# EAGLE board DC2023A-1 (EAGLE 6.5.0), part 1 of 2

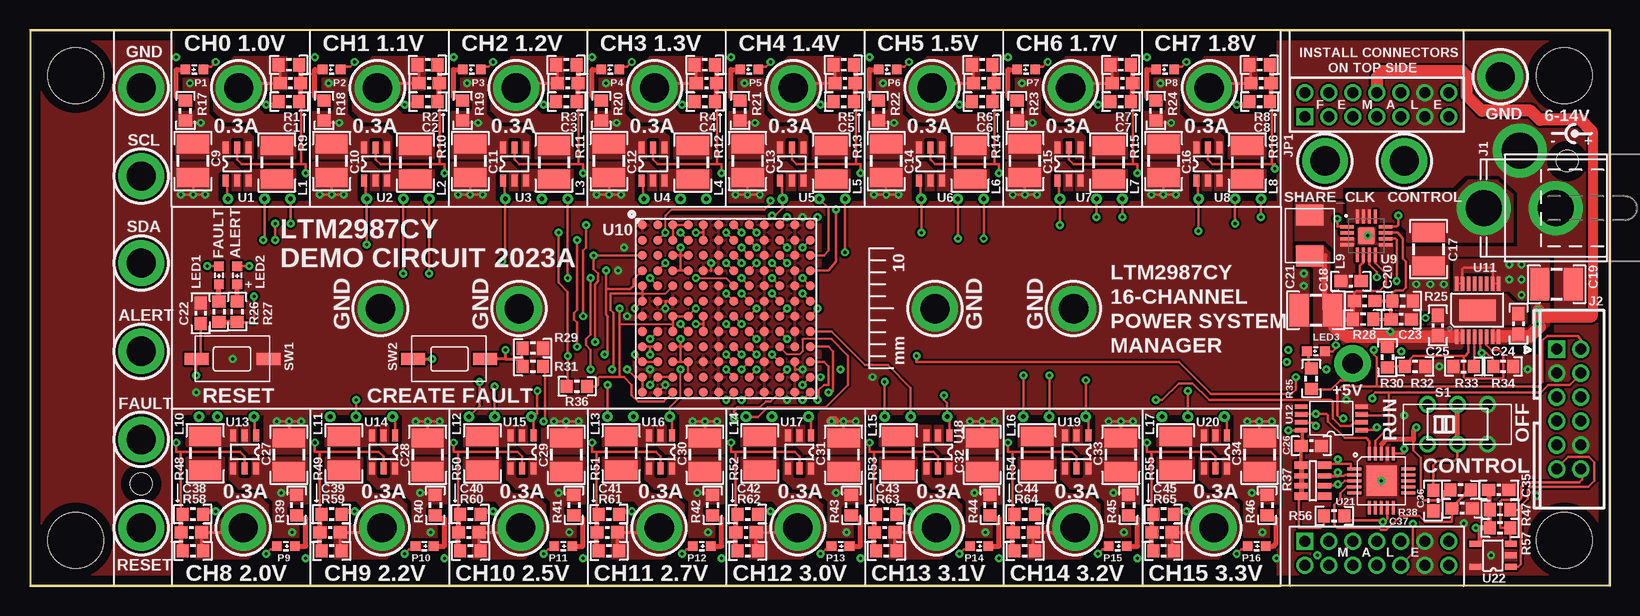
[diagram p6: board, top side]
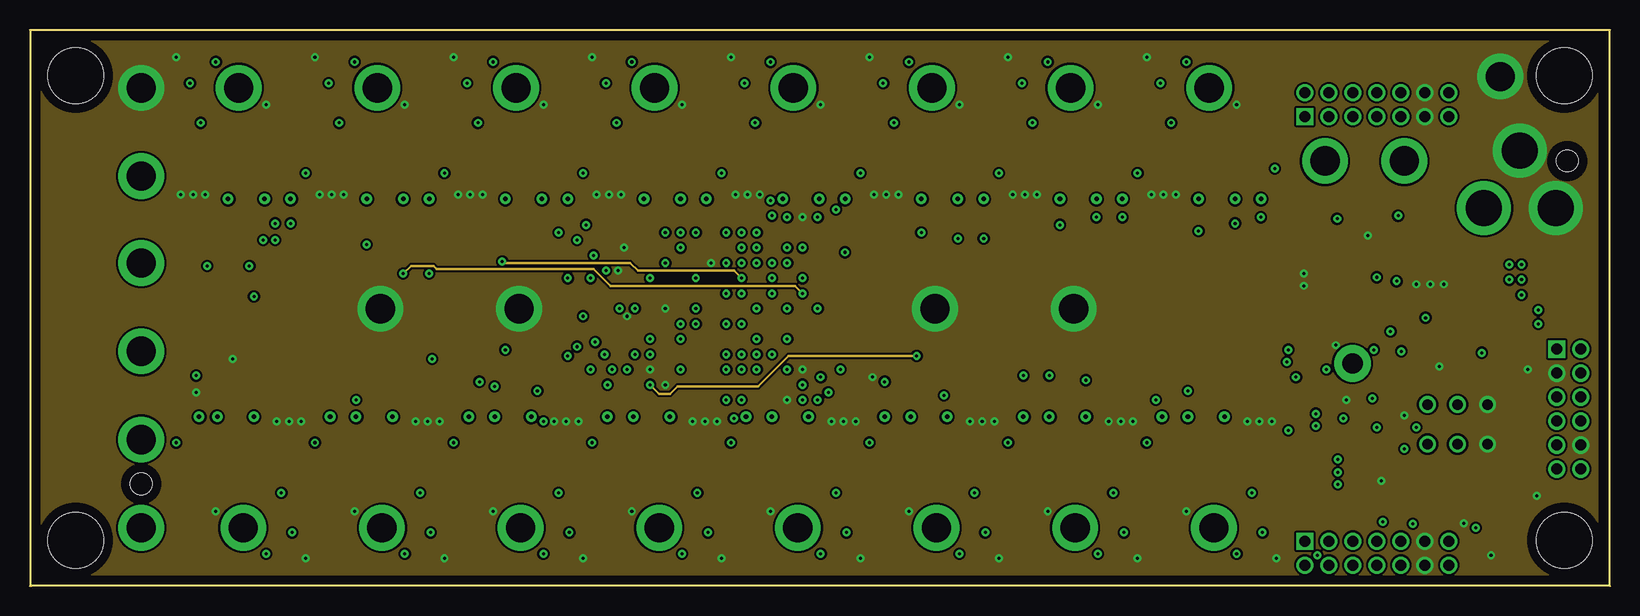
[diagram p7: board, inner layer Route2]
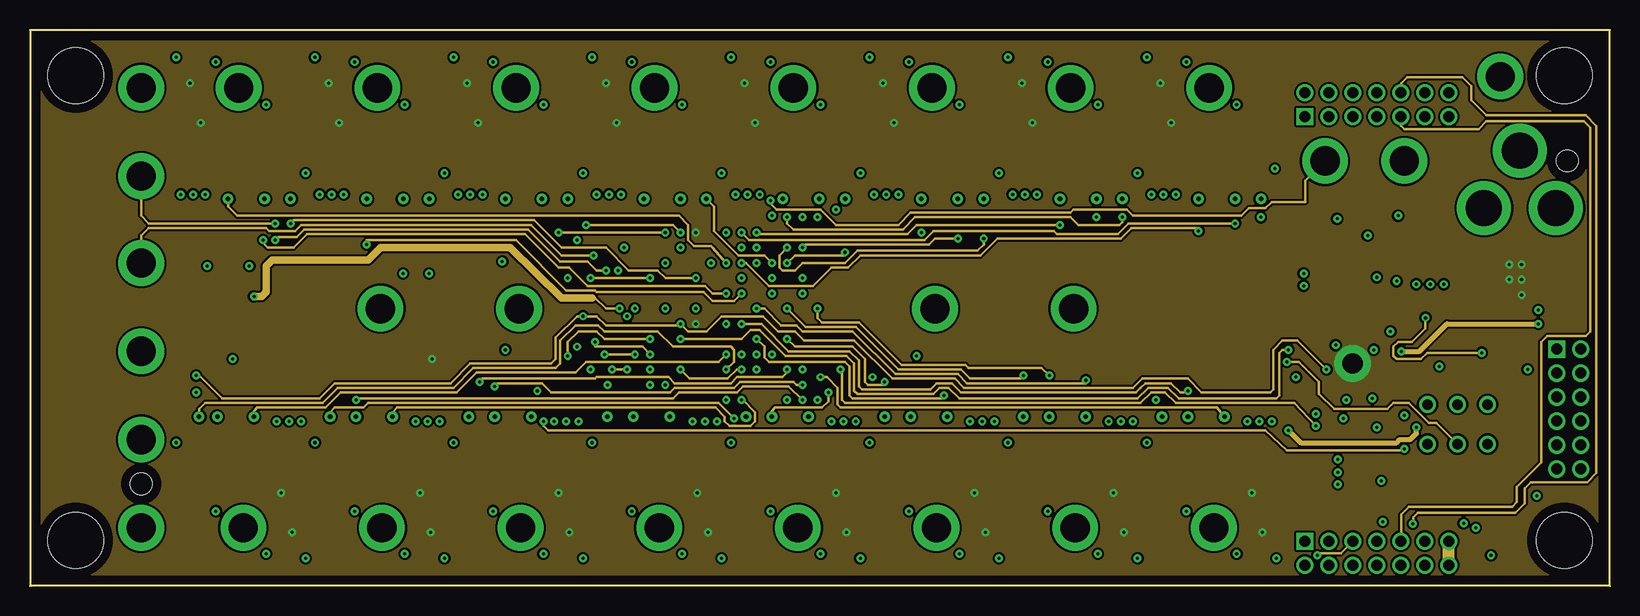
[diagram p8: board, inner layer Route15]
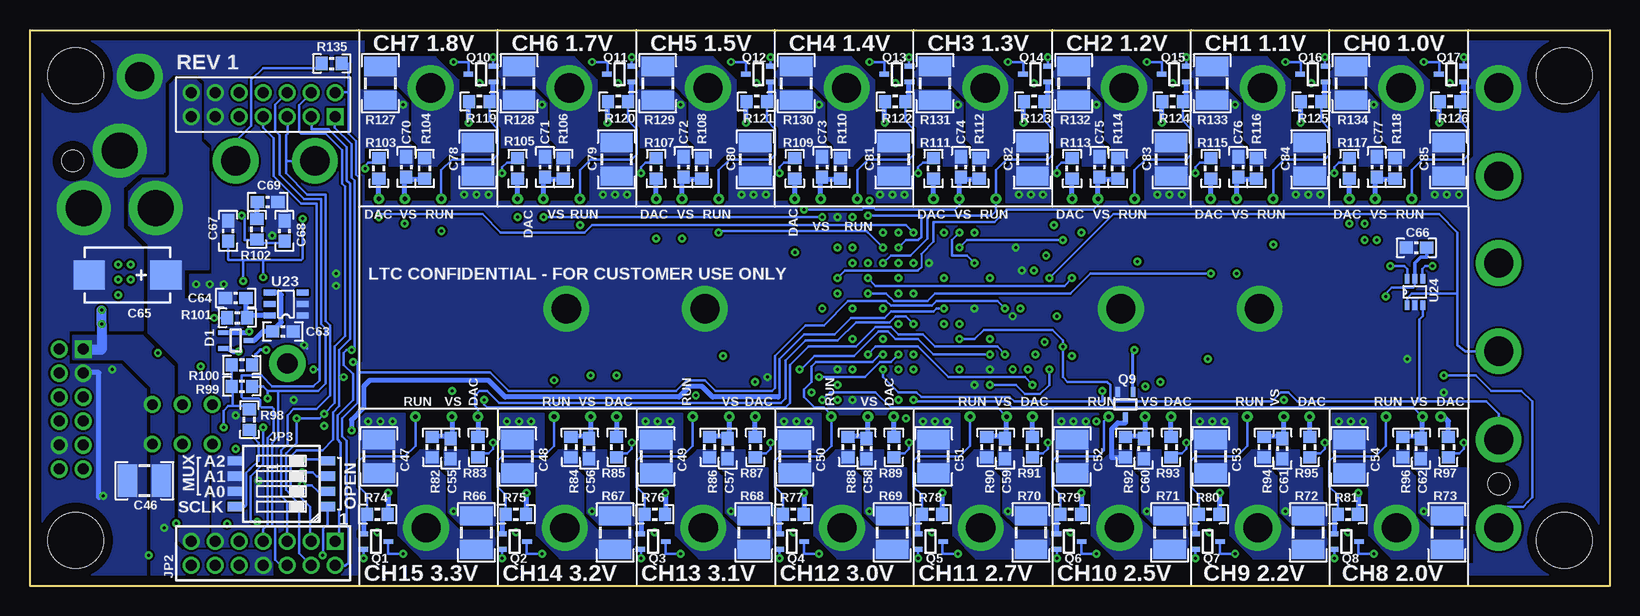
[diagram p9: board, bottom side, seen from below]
Size 131.7 x 46.35 mm. Coordinates in mm from the lower left corner, seen from the top.
Outline: 0,0 0,46.35 131.7,46.35 131.7,0 0.13,0
Copper layers (1*2+15*16): Top 0.035mm / dielectric 1.5mm / Route2 0.035mm / dielectric 0.15mm / Route15 0.035mm / dielectric 0.2mm / Bottom 0.035mm
Design rules "default *": minimum track width 7mil, minimum drill 10mil, track to track 7mil, track to pad 7mil, pad to pad 7mil, via to via 7mil, smd to smd 4mil, copper to edge 30mil, drill to drill 20mil, minimum pad ring 10mil, minimum via ring 8mil, stop-mask expansion 4mil, vias tented up to drill 16mil, thermal gap 10mil
Holes 4.65 mm at 3.81,3.81 3.81,42.55 127.89,42.55 127.89,3.81
Holes 1.8 mm at 9.27,8.51 128.14,35.43

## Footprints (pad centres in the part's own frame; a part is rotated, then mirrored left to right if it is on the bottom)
C0603_BOX = smd 1.1 x 1: 1 -0.85,0; 2 0.85,0
C1210_BOX = smd 1.6 x 2.7: 1 -1.4,0; 2 1.4,0
C7343 = smd 2.6 x 2.4: + -3.2,0; - 3.2,0
SC70-3 = smd 0.4 x 0.8: 1 -0.65,-1.052; 2 0.65,-1.052; 3 0,1.052
PJ-002A = drill 3 pad 4.5: 1 -3,0; 2 0,-4.8; 3 3,0
CONN_DC1613 = drill 0.914 square: 1 -5,-1 | drill 0.914: 2 -5,1; 3 -3,-1; 4 -3,1; 5 -1,-1; 6 -1,1; 7 1,-1; 8 1,1; 9 3,-1; 10 3,1; 11 5,-1; 12 5,1
2X07M = drill 0.914 square: 1 -6,-1 | drill 0.914: 2 -6,1; 3 -4,-1; 4 -4,1; 5 -2,-1; 6 -2,1; 7 0,-1; 8 0,1; 9 2,-1; 10 2,1; 11 4,-1; 12 4,1; 13 6,-1; 14 6,1
SMT_DIP_4 = smd 1.27 x 0.762: 1 -3.861,1.905; 2 -3.861,0.635; 3 -3.861,-0.635; 4 -3.861,-1.905; 5 3.861,-1.905; 6 3.861,-0.635; 7 3.861,0.635; 8 3.861,1.905
L1210 = smd 1.6 x 2.7: 1 -1.4,0; 2 1.4,0
IHLP_1616AB = smd 1.75 x 2.3: 1 -1.7,0; 2 1.7,0
CHIPLED_0603 = smd 0.8 x 0.8: N 0,0.75; P 0,-0.75
R0603_BOX = smd 1 x 1.1: 1 -0.85,0; 2 0.85,0
R_VISHAY_CRA06S = smd 1.15 x 0.63: R1_1 -0.975,1.295; R1_2 0.975,1.295; R4_1 -0.975,-1.295; R4_2 0.975,-1.295 | smd 1.15 x 0.44: R2_1 -0.975,0.4; R2_2 0.975,0.4; R3_1 -0.975,-0.4; R3_2 0.975,-0.4
R1210_BOX = smd 1.6 x 2.7: 1 -1.4,0; 2 1.4,0
JS202011CQN = drill 0.9: 1 -2.5,1.65; 2 0,1.65; 3 2.5,1.65; 4 -2.5,-1.65; 5 0,-1.65; 6 2.5,-1.65
SWITCH_PTS635 = smd 2 x 1: SW1 -3,0; SW2 3,0
TP1 = drill 2.438 pad 3.81: TP 0,0
TURRET_SMALL_2308 = drill 1.702 pad 3.048: TP1 0,0
SOT-23-6 = smd 1 x 0.5: 1 -1.374,1.087; 2 -1.374,0.127; 3 -1.374,-0.833; 4 1.374,-0.833; 5 1.374,0.127; 6 1.374,1.087
QFN16_3X3 = smd 1.2 x 0.3: 1 -1.711,0.734; 2 -1.711,0.234; 3 -1.711,-0.266; 4 -1.711,-0.766; 9 1.489,-0.766; 10 1.489,-0.266; 11 1.489,0.234; 12 1.489,0.734 | smd 0.3 x 1.2: 5 -0.861,-1.616; 6 -0.361,-1.616; 7 0.139,-1.616; 8 0.639,-1.616; 13 0.639,1.584; 14 0.139,1.584; 15 -0.361,1.584; 16 -0.861,1.584 | smd 1.4 x 1.4: PAD -0.111,-0.016
BGA_144_1.27 = smd 0.73 x 0.73: A1 -6.985,-6.985; A2 -6.985,-5.715; A3 -6.985,-4.445; A4 -6.985,-3.175; A5 -6.985,-1.905; A6 -6.985,-0.635; A7 -6.985,0.635; A8 -6.985,1.905; A9 -6.985,3.175; A10 -6.985,4.445; A11 -6.985,5.715; A12 -6.985,6.985; B1 -5.715,-6.985; B2 -5.715,-5.715; B3 -5.715,-4.445; B4 -5.715,-3.175; B5 -5.715,-1.905; B6 -5.715,-0.635; B7 -5.715,0.635; B8 -5.715,1.905; B9 -5.715,3.175; B10 -5.715,4.445; B11 -5.715,5.715; B12 -5.715,6.985; C1 -4.445,-6.985; C2 -4.445,-5.715; C3 -4.445,-4.445; C4 -4.445,-3.175; C5 -4.445,-1.905; C6 -4.445,-0.635; C7 -4.445,0.635; C8 -4.445,1.905; C9 -4.445,3.175; C10 -4.445,4.445; C11 -4.445,5.715; C12 -4.445,6.985; D1 -3.175,-6.985; D2 -3.175,-5.715; D3 -3.175,-4.445; D4 -3.175,-3.175; D5 -3.175,-1.905; D6 -3.175,-0.635; D7 -3.175,0.635; D8 -3.175,1.905; D9 -3.175,3.175; D10 -3.175,4.445; D11 -3.175,5.715; D12 -3.175,6.985; E1 -1.905,-6.985; E2 -1.905,-5.715; E3 -1.905,-4.445; E4 -1.905,-3.175; E5 -1.905,-1.905; E6 -1.905,-0.635; E7 -1.905,0.635; E8 -1.905,1.905; E9 -1.905,3.175; E10 -1.905,4.445; E11 -1.905,5.715; E12 -1.905,6.985; F1 -0.635,-6.985; F2 -0.635,-5.715; F3 -0.635,-4.445; F4 -0.635,-3.175; F5 -0.635,-1.905; F6 -0.635,-0.635; F7 -0.635,0.635; F8 -0.635,1.905; F9 -0.635,3.175; F10 -0.635,4.445; F11 -0.635,5.715; F12 -0.635,6.985; G1 0.635,-6.985; G2 0.635,-5.715; G3 0.635,-4.445; G4 0.635,-3.175; G5 0.635,-1.905; G6 0.635,-0.635; G7 0.635,0.635; G8 0.635,1.905; G9 0.635,3.175; G10 0.635,4.445; G11 0.635,5.715; G12 0.635,6.985; H1 1.905,-6.985; H2 1.905,-5.715; H3 1.905,-4.445; H4 1.905,-3.175; H5 1.905,-1.905; H6 1.905,-0.635; H7 1.905,0.635; H8 1.905,1.905; H9 1.905,3.175; H10 1.905,4.445; H11 1.905,5.715; H12 1.905,6.985; J1 3.175,-6.985; J2 3.175,-5.715; J3 3.175,-4.445; J4 3.175,-3.175; J5 3.175,-1.905; J6 3.175,-0.635; J7 3.175,0.635; J8 3.175,1.905; J9 3.175,3.175; J10 3.175,4.445; J11 3.175,5.715; J12 3.175,6.985; K1 4.445,-6.985; K2 4.445,-5.715; K3 4.445,-4.445; K4 4.445,-3.175; K5 4.445,-1.905; K6 4.445,-0.635; K7 4.445,0.635; K8 4.445,1.905; K9 4.445,3.175; K10 4.445,4.445; K11 4.445,5.715; K12 4.445,6.985; L1 5.715,-6.985; L2 5.715,-5.715; L3 5.715,-4.445; L4 5.715,-3.175; L5 5.715,-1.905; L6 5.715,-0.635; L7 5.715,0.635; L8 5.715,1.905; L9 5.715,3.175; L10 5.715,4.445; L11 5.715,5.715; L12 5.715,6.985; M1 6.985,-6.985; M2 6.985,-5.715; M3 6.985,-4.445; M4 6.985,-3.175; M5 6.985,-1.905; M6 6.985,-0.635; M7 6.985,0.635; M8 6.985,1.905; M9 6.985,3.175; M10 6.985,4.445; M11 6.985,5.715; M12 6.985,6.985
MSOP16_EXP = smd 1.2 x 0.3: 1 -2.213,1.75; 2 -2.213,1.25; 3 -2.213,0.75; 4 -2.213,0.25; 5 -2.213,-0.25; 6 -2.213,-0.75; 7 -2.213,-1.25; 8 -2.213,-1.75; 9 2.213,-1.75; 10 2.213,-1.25; 11 2.213,-0.75; 12 2.213,-0.25; 13 2.213,0.25; 14 2.213,0.75; 15 2.213,1.25; 16 2.213,1.75 | smd 1.778 x 3.048: EXP 0,0
MSOP-8 = smd 1.041 x 0.381: 1 -2.55,0.975; 2 -2.55,0.325; 3 -2.55,-0.325; 4 -2.55,-0.975; 5 2.479,-0.975; 6 2.479,-0.325; 7 2.479,0.325; 8 2.479,0.975
QFN20 = smd 1.143 x 0.254: 1 -2.25,1; 2 -2.25,0.5; 3 -2.25,0; 4 -2.25,-0.5; 5 -2.25,-1; 11 2.25,-1; 12 2.25,-0.5; 13 2.25,0; 14 2.25,0.5; 15 2.25,1 | smd 0.254 x 1.143: 6 -1,-2.25; 7 -0.5,-2.25; 8 0,-2.25; 9 0.5,-2.25; 10 1,-2.25; 16 1,2.25; 17 0.5,2.25; 18 0,2.25; 19 -0.5,2.25; 20 -1,2.25 | smd 2.54 x 2.54: PAD 0,0
SOT-23-5 = smd 1 x 0.5: 1 -1.649,0.95; 2 -1.649,0; 3 -1.649,-0.95; 4 1.333,-0.95; 5 1.333,0.95
SC70-6 = smd 0.4 x 0.8: 1 -0.65,-1.102; 2 0,-1.102; 3 0.65,-1.102; 4 0.65,1.102; 5 0,1.098; 6 -0.65,1.102
VIA = drill 0.381: 1 0,0

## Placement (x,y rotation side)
$$U$1  [LT_LOGO_LARGE_SM]  5.46,6.1 90 top
$$U$2  [LT_LOGO_LARGE_SM]  2.03,6.1 90 bottom
C1  220p  [C0603_BOX]  21.72,41.91 0 top
C2  220p  [C0603_BOX]  33.27,41.91 0 top
C3  220p  [C0603_BOX]  44.83,41.91 0 top
C4  220p  [C0603_BOX]  56.39,41.91 0 top
C5  220p  [C0603_BOX]  67.94,41.91 0 top
C6  220p  [C0603_BOX]  79.5,41.91 0 top
C7  220p  [C0603_BOX]  91.06,41.91 0 top
C8  220p  [C0603_BOX]  102.62,41.91 0 top
C9  10u/10V  [C1210_BOX]  13.59,35.43 270 top
C10  10u/10V  [C1210_BOX]  25.15,35.43 270 top
C11  10u/10V  [C1210_BOX]  36.7,35.43 270 top
C12  10u/10V  [C1210_BOX]  48.26,35.43 270 top
C13  10u/10V  [C1210_BOX]  59.82,35.43 270 top
C14  10u/10V  [C1210_BOX]  71.37,35.43 270 top
C15  10u/10V  [C1210_BOX]  82.93,35.43 270 top
C16  10u/10V  [C1210_BOX]  94.49,35.43 270 top
C17  10u/25V  [C1210_BOX]  116.59,28.07 90 top
C18  100n  [C0603_BOX]  110.11,25.4 0 top
C19  10u/10V  [C1210_BOX]  127.25,25.15 0 top
C20  68p  [C0603_BOX]  111.25,23.75 0 top
C21  22u/10V  [C1210_BOX]  107.19,22.99 180 top
C22  10n  [C0603_BOX]  14.22,22.73 90 top
C23  47p  [C0603_BOX]  114.3,22.23 0 top
C24  1u  [C0603_BOX]  124.08,21.84 90 top
C25  1u  [C0603_BOX]  117.35,21.72 90 top
C26  100n  [C0603_BOX]  106.81,11.68 0 top
C27  10u/10V  [C1210_BOX]  21.59,10.92 90 top
C28  10u/10V  [C1210_BOX]  33.15,10.92 90 top
C29  10u/10V  [C1210_BOX]  44.7,10.92 90 top
C30  10u/10V  [C1210_BOX]  56.26,10.92 90 top
C31  10u/10V  [C1210_BOX]  67.82,10.92 90 top
C32  10u/10V  [C1210_BOX]  79.38,10.92 90 top
C33  10u/10V  [C1210_BOX]  90.93,10.92 90 top
C34  10u/10V  [C1210_BOX]  102.49,10.92 90 top
C35  1u  [C0603_BOX]  122.43,8 0 top
C36  1u  [C0603_BOX]  116.97,7.11 270 top
C37  1u  [C0603_BOX]  119.38,6.48 0 top
C38  220p  [C0603_BOX]  13.46,4.45 180 top
C39  220p  [C0603_BOX]  25.02,4.45 180 top
C40  220p  [C0603_BOX]  36.58,4.45 180 top
C41  220p  [C0603_BOX]  48.13,4.45 180 top
C42  220p  [C0603_BOX]  59.69,4.45 180 top
C43  220p  [C0603_BOX]  71.25,4.45 180 top
C44  220p  [C0603_BOX]  82.8,4.45 180 top
C45  220p  [C0603_BOX]  94.36,4.45 180 top
C46  10u/10V  [C1210_BOX]  122.17,8.76 180 bottom
C47  22u/10V  [C1210_BOX]  102.62,10.79 90 bottom
C48  22u/10V  [C1210_BOX]  91.06,10.79 90 bottom
C49  22u/10V  [C1210_BOX]  79.5,10.79 90 bottom
C50  22u/10V  [C1210_BOX]  67.94,10.79 90 bottom
C51  22u/10V  [C1210_BOX]  56.39,10.79 90 bottom
C52  22u/10V  [C1210_BOX]  44.83,10.79 90 bottom
C53  22u/10V  [C1210_BOX]  33.27,10.79 90 bottom
C54  22u/10V  [C1210_BOX]  21.72,10.79 90 bottom
C55  OPT  [C0603_BOX]  96.65,11.43 90 bottom
C56  OPT  [C0603_BOX]  85.09,11.43 90 bottom
C57  OPT  [C0603_BOX]  73.53,11.43 90 bottom
C58  OPT  [C0603_BOX]  61.98,11.43 90 bottom
C59  OPT  [C0603_BOX]  50.42,11.43 90 bottom
C60  OPT  [C0603_BOX]  38.86,11.43 90 bottom
C61  OPT  [C0603_BOX]  27.3,11.43 90 bottom
C62  OPT  [C0603_BOX]  15.75,11.43 90 bottom
C63  1u  [C0603_BOX]  110.62,21.21 0 bottom
C64  4.7u  [C0603_BOX]  114.55,24 0 bottom
C65  47u/16V  [C7343]  123.57,25.91 180 bottom
C66  1u  [C0603_BOX]  16.13,28.19 180 bottom
C67  4.7u  [C0603_BOX]  115.19,29.59 90 bottom
C68  4.7p  [C0603_BOX]  110.49,29.59 90 bottom
C69  68p  [C0603_BOX]  111.89,32 0 bottom
C70  OPT  [C0603_BOX]  100.33,34.92 270 bottom
C71  OPT  [C0603_BOX]  88.77,34.92 270 bottom
C72  OPT  [C0603_BOX]  77.22,34.92 270 bottom
C73  OPT  [C0603_BOX]  65.66,34.92 270 bottom
C74  OPT  [C0603_BOX]  54.1,34.92 270 bottom
C75  OPT  [C0603_BOX]  42.55,34.92 270 bottom
C76  OPT  [C0603_BOX]  30.99,34.92 270 bottom
C77  OPT  [C0603_BOX]  19.43,34.92 270 bottom
C78  22u/10V  [C1210_BOX]  94.36,35.56 270 bottom
C79  22u/10V  [C1210_BOX]  82.8,35.56 270 bottom
C80  22u/10V  [C1210_BOX]  71.25,35.56 270 bottom
C81  22u/10V  [C1210_BOX]  59.69,35.56 270 bottom
C82  22u/10V  [C1210_BOX]  48.13,35.56 270 bottom
C83  22u/10V  [C1210_BOX]  36.58,35.56 270 bottom
C84  22u/10V  [C1210_BOX]  25.02,35.56 270 bottom
C85  22u/10V  [C1210_BOX]  13.46,35.56 270 bottom
D1  BAT30CWFILM  [SC70-3]  114.55,20.45 270 bottom
DRILEGEND  [DRILEGEND]  not placed on the board
J1  PJ-002A  [PJ-002A]  124.21,31.5 180 top
J2  CONN_DC1613  [CONN_DC1613]  128.27,14.73 270 top
JP1  FEMALE  [2X07M]  112.27,40.13 0 top
JP2  MALE  [2X07M]  112.27,2.72 180 bottom
JP3  TDA04H0SK1  [SMT_DIP_4]  110.74,8.51 0 bottom
L1  4.7uH  [L1210]  20.57,35.31 90 top
L2  4.7uH  [L1210]  32.13,35.31 90 top
L3  4.7uH  [L1210]  43.69,35.31 90 top
L4  4.7uH  [L1210]  55.24,35.31 90 top
L5  4.7uH  [L1210]  66.8,35.31 90 top
L6  4.7uH  [L1210]  78.36,35.31 90 top
L7  4.7uH  [L1210]  89.92,35.31 90 top
L8  4.7uH  [L1210]  101.47,35.31 90 top
L9  2.2uH  [IHLP_1616AB]  106.68,29.21 270 top
L10  4.7uH  [L1210]  14.61,11.05 270 top
L11  4.7uH  [L1210]  26.16,11.05 270 top
L12  4.7uH  [L1210]  37.72,11.05 270 top
L13  4.7uH  [L1210]  49.28,11.05 270 top
L14  4.7uH  [L1210]  60.83,11.05 270 top
L15  4.7uH  [L1210]  72.39,11.05 270 top
L16  4.7uH  [L1210]  83.95,11.05 270 top
L17  4.7uH  [L1210]  95.5,11.05 270 top
LED1  RED  [CHIPLED_0603]  15.75,25.91 0 top
LED2  RED  [CHIPLED_0603]  17.27,25.91 0 top
LED3  GREEN  [CHIPLED_0603]  107.19,19.56 270 top
P1  GREEN  [CHIPLED_0603]  13.72,43.05 270 top
P2  GREEN  [CHIPLED_0603]  25.15,43.05 270 top
P3  GREEN  [CHIPLED_0603]  36.83,43.05 270 top
P4  GREEN  [CHIPLED_0603]  48.39,43.05 270 top
P5  GREEN  [CHIPLED_0603]  59.94,43.05 270 top
P6  GREEN  [CHIPLED_0603]  71.5,43.05 270 top
P7  GREEN  [CHIPLED_0603]  83.06,43.05 270 top
P8  GREEN  [CHIPLED_0603]  94.61,43.05 270 top
P9  GREEN  [CHIPLED_0603]  21.34,3.3 90 top
P10  GREEN  [CHIPLED_0603]  32.89,3.3 90 top
P11  GREEN  [CHIPLED_0603]  44.45,3.3 90 top
P12  GREEN  [CHIPLED_0603]  56.01,3.3 90 top
P13  GREEN  [CHIPLED_0603]  67.56,3.3 90 top
P14  GREEN  [CHIPLED_0603]  79.12,3.3 90 top
P15  GREEN  [CHIPLED_0603]  90.68,3.3 90 top
P16  GREEN  [CHIPLED_0603]  102.23,3.3 90 top
Q1  DMG1012UW-7  [SC70-3]  102.87,3.68 270 bottom
Q2  DMG1012UW-7  [SC70-3]  91.31,3.68 270 bottom
Q3  DMG1012UW-7  [SC70-3]  79.76,3.68 270 bottom
Q4  DMG1012UW-7  [SC70-3]  68.2,3.68 270 bottom
Q5  DMG1012UW-7  [SC70-3]  56.64,3.68 270 bottom
Q6  DMG1012UW-7  [SC70-3]  45.09,3.68 270 bottom
Q7  DMG1012UW-7  [SC70-3]  33.53,3.68 270 bottom
Q8  DMG1012UW-7  [SC70-3]  21.97,3.68 270 bottom
Q9  DMG1012UW-7  [SC70-3]  40.39,15.11 180 bottom
Q10  DMG1012UW-7  [SC70-3]  94.11,42.67 90 bottom
Q11  DMG1012UW-7  [SC70-3]  82.55,42.67 90 bottom
Q12  DMG1012UW-7  [SC70-3]  70.99,42.67 90 bottom
Q13  DMG1012UW-7  [SC70-3]  59.44,42.67 90 bottom
Q14  DMG1012UW-7  [SC70-3]  47.88,42.67 90 bottom
Q15  DMG1012UW-7  [SC70-3]  36.32,42.67 90 bottom
Q16  DMG1012UW-7  [SC70-3]  24.77,42.67 90 bottom
Q17  DMG1012UW-7  [SC70-3]  13.21,42.67 90 bottom
R1  100k  [R0603_BOX]  21.59,43.43 180 top
R2  100k  [R0603_BOX]  33.15,43.43 180 top
R3  100k  [R0603_BOX]  44.7,43.43 180 top
R4  100k  [R0603_BOX]  56.26,43.43 180 top
R5  100k  [R0603_BOX]  67.82,43.43 180 top
R6  100k  [R0603_BOX]  79.38,43.43 180 top
R7  100k  [R0603_BOX]  90.93,43.43 180 top
R8  100k  [R0603_BOX]  102.49,43.43 180 top
R9  402k  [R0603_BOX]  21.59,40.39 0 top
R10  267k  [R0603_BOX]  33.15,40.39 0 top
R11  200k  [R0603_BOX]  44.7,40.39 0 top
R12  158k  [R0603_BOX]  56.26,40.39 0 top
R13  133k  [R0603_BOX]  67.82,40.39 0 top
R14  115k  [R0603_BOX]  79.38,40.39 0 top
R15  88.7k  [R0603_BOX]  90.93,40.39 0 top
R16  80.6k  [R0603_BOX]  102.49,40.39 0 top
R17  3.01k  [R0603_BOX]  12.95,39.62 270 top
R18  3.01k  [R0603_BOX]  24.51,39.62 270 top
R19  3.01k  [R0603_BOX]  36.07,39.62 270 top
R20  3.01k  [R0603_BOX]  47.62,39.62 270 top
R21  3.01k  [R0603_BOX]  59.18,39.62 270 top
R22  3.01k  [R0603_BOX]  70.74,39.62 270 top
R23  3.01k  [R0603_BOX]  82.3,39.62 270 top
R24  3.01k  [R0603_BOX]  93.85,39.62 270 top
R25  10k  [R0603_BOX]  114.43,23.75 180 top
R26  698  [R0603_BOX]  15.75,22.86 90 top
R27  698  [R0603_BOX]  17.27,22.86 270 top
R28  73.2k  [R0603_BOX]  111.12,22.23 180 top
R29  100k  [R0603_BOX]  41.91,19.81 180 top
R30  46.4k  [R0603_BOX]  113.16,19.05 90 top
R31  OPT  [R0603_BOX]  41.91,18.29 180 top
R32  10k  [R0603_BOX]  115.44,18.29 180 top
R33  249  [R0603_BOX]  119.51,18.29 0 top
R34  1.0k  [R0603_BOX]  122.81,18.29 180 top
R35  3.01k  [R0603_BOX]  106.81,17.27 270 top
R36  10k  [R0603_BOX]  45.59,16.64 0 top
R37  10k, 4X  [R_VISHAY_CRA06S]  106.93,8.76 180 top
R38  249  [R0603_BOX]  119.25,8 0 top
R39  3.01k  [R0603_BOX]  22.23,6.73 90 top
R40  3.01k  [R0603_BOX]  33.78,6.73 90 top
R41  3.01k  [R0603_BOX]  45.34,6.73 90 top
R42  3.01k  [R0603_BOX]  56.9,6.73 90 top
R43  3.01k  [R0603_BOX]  68.45,6.73 90 top
R44  3.01k  [R0603_BOX]  80.01,6.73 90 top
R45  3.01k  [R0603_BOX]  91.57,6.73 90 top
R46  3.01k  [R0603_BOX]  103.12,6.73 90 top
R47  10k  [R0603_BOX]  122.56,6.35 180 top
R48  66.5k  [R0603_BOX]  13.59,5.97 180 top
R49  57.6k  [R0603_BOX]  25.15,5.97 180 top
R50  47.5k  [R0603_BOX]  36.7,5.97 180 top
R51  42.2k  [R0603_BOX]  48.26,5.97 180 top
R52  36.5k  [R0603_BOX]  59.82,5.97 180 top
R53  34.8k  [R0603_BOX]  71.37,5.97 180 top
R54  33.2k  [R0603_BOX]  82.93,5.97 180 top
R55  32.4k  [R0603_BOX]  94.49,5.97 180 top
R56  10k  [R0603_BOX]  108.71,5.84 0 top
R57  10k  [R0603_BOX]  122.56,4.83 180 top
R58  100k  [R0603_BOX]  13.59,2.92 0 top
R59  100k  [R0603_BOX]  25.15,2.92 0 top
R60  100k  [R0603_BOX]  36.7,2.92 0 top
R61  100k  [R0603_BOX]  48.26,2.92 0 top
R62  100k  [R0603_BOX]  59.82,2.92 0 top
R63  100k  [R0603_BOX]  71.37,2.92 0 top
R64  100k  [R0603_BOX]  82.93,2.92 0 top
R65  100k  [R0603_BOX]  94.49,2.92 0 top
R66  470  [R1210_BOX]  94.49,4.45 270 bottom
R67  470  [R1210_BOX]  82.93,4.45 270 bottom
R68  470  [R1210_BOX]  71.37,4.45 270 bottom
R69  470  [R1210_BOX]  59.82,4.45 270 bottom
R70  470  [R1210_BOX]  48.26,4.45 270 bottom
R71  470  [R1210_BOX]  36.7,4.45 270 bottom
R72  470  [R1210_BOX]  25.15,4.45 270 bottom
R73  470  [R1210_BOX]  13.59,4.45 270 bottom
R74  100k  [R0603_BOX]  102.74,5.97 0 bottom
R75  100k  [R0603_BOX]  91.19,5.97 0 bottom
R76  100k  [R0603_BOX]  79.63,5.97 0 bottom
R77  100k  [R0603_BOX]  68.07,5.97 0 bottom
R78  100k  [R0603_BOX]  56.52,5.97 0 bottom
R79  100k  [R0603_BOX]  44.96,5.97 0 bottom
R80  100k  [R0603_BOX]  33.4,5.97 0 bottom
R81  100k  [R0603_BOX]  21.84,5.97 0 bottom
R82  0  [R0603_BOX]  98.17,11.56 90 bottom
R83  182k  [R0603_BOX]  94.36,11.56 90 bottom
R84  0  [R0603_BOX]  86.61,11.56 90 bottom
R85  191k  [R0603_BOX]  82.8,11.56 90 bottom
R86  0  [R0603_BOX]  75.06,11.56 90 bottom
R87  196k  [R0603_BOX]  71.25,11.56 90 bottom
R88  0  [R0603_BOX]  63.5,11.56 90 bottom
R89  205k  [R0603_BOX]  59.69,11.56 90 bottom
R90  0  [R0603_BOX]  51.94,11.56 90 bottom
R91  226k  [R0603_BOX]  48.13,11.56 90 bottom
R92  0  [R0603_BOX]  40.39,11.56 90 bottom
R93  243k  [R0603_BOX]  36.58,11.56 90 bottom
R94  0  [R0603_BOX]  28.83,11.56 90 bottom
R95  274k  [R0603_BOX]  25.02,11.56 90 bottom
R96  0  [R0603_BOX]  17.27,11.56 90 bottom
R97  301k  [R0603_BOX]  13.46,11.56 90 bottom
R98  10k  [R0603_BOX]  113.41,13.84 270 bottom
R99  10k  [R0603_BOX]  114.05,16.64 0 bottom
R100  10k  [R0603_BOX]  114.05,18.41 0 bottom
R101  2.49k  [R0603_BOX]  114.43,22.35 0 bottom
R102  73.2k  [R0603_BOX]  112.78,29.72 270 bottom
R103  340k  [R0603_BOX]  102.62,34.8 270 bottom
R104  0  [R0603_BOX]  98.81,34.8 270 bottom
R105  357k  [R0603_BOX]  91.06,34.8 270 bottom
R106  0  [R0603_BOX]  87.25,34.8 270 bottom
R107  402k  [R0603_BOX]  79.5,34.8 270 bottom
R108  0  [R0603_BOX]  75.69,34.8 270 bottom
R109  374k  [R0603_BOX]  67.94,34.8 270 bottom
R110  0  [R0603_BOX]  64.14,34.8 270 bottom
R111  464k  [R0603_BOX]  56.39,34.8 270 bottom
R112  0  [R0603_BOX]  52.58,34.8 270 bottom
R113  511k  [R0603_BOX]  44.83,34.8 270 bottom
R114  0  [R0603_BOX]  41.02,34.8 270 bottom
R115  549k  [R0603_BOX]  33.27,34.8 270 bottom
R116  0  [R0603_BOX]  29.46,34.8 270 bottom
R117  604k  [R0603_BOX]  21.72,34.8 270 bottom
R118  0  [R0603_BOX]  17.91,34.8 270 bottom
R119  100k  [R0603_BOX]  94.23,40.39 180 bottom
R120  100k  [R0603_BOX]  82.68,40.39 180 bottom
R121  100k  [R0603_BOX]  71.12,40.39 180 bottom
R122  100k  [R0603_BOX]  59.56,40.39 180 bottom
R123  100k  [R0603_BOX]  48.01,40.39 180 bottom
R124  100k  [R0603_BOX]  36.45,40.39 180 bottom
R125  100k  [R0603_BOX]  24.89,40.39 180 bottom
R126  100k  [R0603_BOX]  13.34,40.39 180 bottom
R127  470  [R1210_BOX]  102.49,41.91 90 bottom
R128  470  [R1210_BOX]  90.93,41.91 90 bottom
R129  470  [R1210_BOX]  79.38,41.91 90 bottom
R130  470  [R1210_BOX]  67.82,41.91 90 bottom
R131  470  [R1210_BOX]  56.26,41.91 90 bottom
R132  470  [R1210_BOX]  44.7,41.91 90 bottom
R133  470  [R1210_BOX]  33.15,41.91 90 bottom
R134  470  [R1210_BOX]  21.59,41.91 90 bottom
R135  10k  [R0603_BOX]  106.55,43.56 0 bottom
S1  CONTROL  [JS202011CQN]  119,13.46 0 top
SW1  PTS635SL25SMTR LFS  [SWITCH_PTS635]  16.89,18.92 0 top
SW2  PTS635SK25SMTR LFS  [SWITCH_PTS635]  34.92,18.92 180 top
TP1  TESTPOINT_BIG  [TP1]  122.56,42.47 0 top
TP2  TESTPOINT_BIG  [TP1]  9.27,41.53 0 top
TP3  TESTPOINT_BIG  [TP1]  17.4,41.53 90 top
TP4  TESTPOINT_BIG  [TP1]  28.96,41.53 90 top
TP5  TESTPOINT_BIG  [TP1]  40.51,41.53 90 top
TP6  TESTPOINT_BIG  [TP1]  52.07,41.53 90 top
TP7  TESTPOINT_BIG  [TP1]  63.63,41.53 90 top
TP8  TESTPOINT_BIG  [TP1]  75.18,41.53 90 top
TP9  TESTPOINT_BIG  [TP1]  86.74,41.53 90 top
TP10  TESTPOINT_BIG  [TP1]  98.3,41.53 90 top
TP11  TESTPOINT_BIG  [TP1]  107.95,35.43 0 top
TP12  TESTPOINT_BIG  [TP1]  114.55,35.43 0 top
TP13  TESTPOINT_BIG  [TP1]  9.27,34.16 0 top
TP14  TESTPOINT_BIG  [TP1]  9.27,26.92 0 top
TP15  TESTPOINT_BIG  [TP1]  29.21,23.11 0 top
TP16  TESTPOINT_BIG  [TP1]  40.77,23.11 0 top
TP17  TESTPOINT_BIG  [TP1]  75.44,23.11 0 top
TP18  TESTPOINT_BIG  [TP1]  87,23.11 0 top
TP19  TESTPOINT_BIG  [TP1]  9.27,19.56 0 top
TP20  TURRET_SMALL_2308TP  [TURRET_SMALL_2308]  110.24,18.54 0 top
TP21  TESTPOINT_BIG  [TP1]  9.27,12.19 0 top
TP22  TESTPOINT_BIG  [TP1]  9.27,4.83 0 top
TP23  TESTPOINT_BIG  [TP1]  17.78,4.83 270 top
TP24  TESTPOINT_BIG  [TP1]  29.34,4.83 270 top
TP25  TESTPOINT_BIG  [TP1]  40.89,4.83 270 top
TP26  TESTPOINT_BIG  [TP1]  52.45,4.83 270 top
TP27  TESTPOINT_BIG  [TP1]  64.01,4.83 270 top
TP28  TESTPOINT_BIG  [TP1]  75.56,4.83 270 top
TP29  TESTPOINT_BIG  [TP1]  87.12,4.83 270 top
TP30  TESTPOINT_BIG  [TP1]  98.68,4.83 270 top
U1  LTC3405AES6  [SOT-23-6]  17.4,35.18 90 top
U2  LTC3405AES6  [SOT-23-6]  28.96,35.18 90 top
U3  LTC3405AES6  [SOT-23-6]  40.51,35.18 90 top
U4  LTC3405AES6  [SOT-23-6]  52.07,35.18 90 top
U5  LTC3405AES6  [SOT-23-6]  63.63,35.18 90 top
U6  LTC3405AES6  [SOT-23-6]  75.18,35.18 90 top
U7  LTC3405AES6  [SOT-23-6]  86.74,35.18 90 top
U8  LTC3405AES6  [SOT-23-6]  98.3,35.18 90 top
U9  LTC3604IUD  [QFN16_3X3]  111.51,29.21 0 top
U10  LTM2987CY  [BGA_144_1.27]  58.04,23.11 270 top
U11  LTC4415IMSE  [MSOP16_EXP]  120.65,22.99 90 top
U12  LTC4313CMS8  [MSOP-8]  108.46,13.97 180 top
U13  LTC3405AES6  [SOT-23-6]  17.78,11.18 270 top
U14  LTC3405AES6  [SOT-23-6]  29.34,11.18 270 top
U15  LTC3405AES6  [SOT-23-6]  40.89,11.18 270 top
U16  LTC3405AES6  [SOT-23-6]  52.45,11.18 270 top
U17  LTC3405AES6  [SOT-23-6]  64.01,11.18 270 top
U18  LTC3405AES6  [SOT-23-6]  75.56,11.18 270 top
U19  LTC3405AES6  [SOT-23-6]  87.12,11.18 270 top
U20  LTC3405AES6  [SOT-23-6]  98.68,11.18 270 top
U21  MCP23008-E/ML  [QFN20]  112.65,8.76 0 top
U22  24AA02T-I/OT  [SOT-23-5]  121.79,2.54 180 top
U23  LT6654BMPS6-1.25  [SOT-23-6]  110.36,23.62 180 bottom
U24  SN74LVC2G34DCK  [SC70-6]  16.26,24.51 0 bottom
U$49  [RULER]  69.98,18.16 90 top
U$73  [DC2023_FRAME]  not placed on the board
VSNSN1  TESPOINT_SMD  [VIA]  16.51,32.26 180 top
VSNSN2  TESPOINT_SMD  [VIA]  28.07,32.26 180 top
VSNSN3  TESPOINT_SMD  [VIA]  39.62,32.26 180 top
VSNSN4  TESPOINT_SMD  [VIA]  51.18,32.26 180 top
VSNSN5  TESPOINT_SMD  [VIA]  62.74,32.26 180 top
VSNSN6  TESPOINT_SMD  [VIA]  74.3,32.26 180 top
VSNSN7  TESPOINT_SMD  [VIA]  85.85,32.26 180 top
VSNSN8  TESPOINT_SMD  [VIA]  97.41,32.26 180 top
VSNSN9  TESPOINT_SMD  [VIA]  18.67,14.1 0 top
VSNSN10  TESPOINT_SMD  [VIA]  30.23,14.1 0 top
VSNSN11  TESPOINT_SMD  [VIA]  41.78,14.1 0 top
VSNSN12  TESPOINT_SMD  [VIA]  53.34,14.1 0 top
VSNSN13  TESPOINT_SMD  [VIA]  64.9,14.1 0 top
VSNSN14  TESPOINT_SMD  [VIA]  76.45,14.1 0 top
VSNSN15  TESPOINT_SMD  [VIA]  88.01,14.1 0 top
VSNSN16  TESPOINT_SMD  [VIA]  99.57,14.1 0 top
VSNSN17  TESPOINT_SMD  [VIA]  96.52,14.1 0 bottom
VSNSN18  TESPOINT_SMD  [VIA]  94.36,14.1 0 bottom
VSNSN19  TESPOINT_SMD  [VIA]  84.96,14.1 0 bottom
VSNSN20  TESPOINT_SMD  [VIA]  82.8,14.1 0 bottom
VSNSN21  TESPOINT_SMD  [VIA]  73.41,14.1 0 bottom
VSNSN22  TESPOINT_SMD  [VIA]  71.25,14.1 0 bottom
VSNSN23  TESPOINT_SMD  [VIA]  61.85,14.1 0 bottom
VSNSN24  TESPOINT_SMD  [VIA]  59.69,14.1 0 bottom
VSNSN25  TESPOINT_SMD  [VIA]  50.29,14.1 0 bottom
VSNSN26  TESPOINT_SMD  [VIA]  48.13,14.1 0 bottom
VSNSN27  TESPOINT_SMD  [VIA]  38.73,14.1 0 bottom
VSNSN28  TESPOINT_SMD  [VIA]  36.58,14.1 0 bottom
VSNSN29  TESPOINT_SMD  [VIA]  27.18,14.1 0 bottom
VSNSN30  TESPOINT_SMD  [VIA]  25.02,14.1 0 bottom
VSNSN31  TESPOINT_SMD  [VIA]  15.62,14.1 0 bottom
VSNSN32  TESPOINT_SMD  [VIA]  14.1,14.1 0 bottom
VSNSN33  TESPOINT_SMD  [VIA]  102.62,32.26 180 bottom
VSNSN34  TESPOINT_SMD  [VIA]  100.46,32.26 180 bottom
VSNSN35  TESPOINT_SMD  [VIA]  91.06,32.26 180 bottom
VSNSN36  TESPOINT_SMD  [VIA]  88.9,32.26 180 bottom
VSNSN37  TESPOINT_SMD  [VIA]  79.5,32.26 180 bottom
VSNSN38  TESPOINT_SMD  [VIA]  77.34,32.26 180 bottom
VSNSN39  TESPOINT_SMD  [VIA]  67.94,32.26 180 bottom
VSNSN40  TESPOINT_SMD  [VIA]  65.79,32.26 180 bottom
VSNSN41  TESPOINT_SMD  [VIA]  56.39,32.26 180 bottom
VSNSN42  TESPOINT_SMD  [VIA]  54.23,32.26 180 bottom
VSNSN43  TESPOINT_SMD  [VIA]  44.83,32.26 180 bottom
VSNSN44  TESPOINT_SMD  [VIA]  42.67,32.26 180 bottom
VSNSN45  TESPOINT_SMD  [VIA]  33.27,32.26 180 bottom
VSNSN46  TESPOINT_SMD  [VIA]  31.11,32.26 180 bottom
VSNSN47  TESPOINT_SMD  [VIA]  21.72,32.26 180 bottom
VSNSN48  TESPOINT_SMD  [VIA]  19.56,32.26 180 bottom

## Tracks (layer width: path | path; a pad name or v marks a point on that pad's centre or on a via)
+3V3  (via drill 0.25)
  Top 0.178: 49.15,21.84 53.59,21.84
  Top 0.203: R56.1 107.86,5.12 107.57,4.83 105.79,4.83 105.79,7.49 105.56,7.47 R37.R1_2 | U12.8 105.75,12.99 105.79,12.95 v104.9,12.95 | 112.65,11.81 U21.18 | R38.1 117.86,7.87 117.86,7.37 117.6,7.11 116.2,7.11 115.95,7.37 115.95,10.67 115.32,11.3 115.32,12.19 | U10.H3 53.59,21.84 U10.G3 U10.G4 v55.5,23.11 | R26.1 15.96,22.01 | 17.23,21.91 17.14,22 15.98,22 15.96,22.01 | 15.96,22.01 15.95,22.02 | v18.67,24.13 18.67,21.97 17.31,21.97 R27.2 | U10.M3 52.83,15.37 50.67,15.37 50.16,15.88 50.16,16.76 49.53,17.4 49.15,17.4 | v49.15,23.11 49.15,21.84 49.15,17.4 | R36.2 47.24,16.64 47.37,16.76 47.37,17.27 47.5,17.4 49.15,17.4
  Top 0.305: U12.8 106.05,12.95 106.05,11.94 106.02,11.92 105.72,11.92 C26.1 R37.R4_2
  Top 0.406: R37.R1_2 R37.R2_2 R37.R3_2 R37.R4_2 | 112.65,11.81 113.03,12.19 115.32,12.19 115.32,12.95 v115.57,13.21 | R26.1 R27.2
  Route15 0.203: v49.15,23.11 48.01,23.11 47.12,24 46.86,24
  Route15 0.406: v115.57,13.21 115.57,12.7 115.06,12.19 114.17,12.19 113.92,11.94 105.92,11.94 v104.9,12.95 104.94,12.99
  Route15 0.61: 46.86,24 44.32,24 40.01,28.19 29.21,28.19 28.19,27.18 20.19,27.18 19.68,26.67 19.68,24.51 19.3,24.13 v18.67,24.13
  Bottom 0.203: R100.1 R99.1 114.9,16.6 114.81,16.51 114.81,14.99 | v115.57,13.21 115.57,14.61 115.19,14.99 114.81,14.99 | U24.5 16.26,25.02 16.38,24.89 18.16,24.89 18.67,24.38 v18.67,24.13 | v55.5,23.11 56.13,23.11 56.39,22.86 59.94,22.86 60.45,22.35 63.25,22.35 64.64,20.95 67.18,20.95 69.22,18.92 69.22,15.75 69.34,15.75 | R98.1 113.41,14.99 114.81,14.99
  Bottom 0.305: U24.5 16.26,26.92 15.75,27.43 15.24,27.43 15.28,27.47 C66.1
  Bottom 0.406: v104.9,12.95 104.9,13.84 103.89,14.86 103.89,16.64 103.38,17.14 93.47,17.14 92.08,15.75 77.6,15.75 76.71,16.64 75.69,16.64 74.8,15.75 69.34,15.75
+12V
  Route15 1.016: JP2.14 JP2.13
  pour Top (no thermals): 109.86,30.3 109.86,32.77 118.87,32.77 119.89,33.78 122.3,33.78 123.57,32.64 123.57,28.7 114.81,28.7 114.81,29.59 114.05,30.35 111.76,30.35
  pour Bottom (no thermals): 116.84,26.42 116.84,36.45 117.47,37.08 117.47,41.78 117.86,42.16 119.63,42.16 120.02,41.78 120.02,34.29 120.4,33.91 122.3,33.91 123.44,32.89 123.44,30.1 121.79,28.45 121.79,21.08 119.25,18.54 119.25,3.81 118.75,3.3 116.84,3.3 116.84,23.88 118.87,23.88 118.87,26.42
A0_MUX  (via drill 0.25)
  Top 0.203: U21.3 109.6,8.76 109.17,8.38 109.02,8.38 v109.02,8.46 109.02,8.41 108.99,8.38 108.56,8.38 | 108.56,8.38 R37.R2_1 108.31,8.36 108.33,8.38 108.56,8.38
  Bottom 0.203: v109.02,8.46 109.02,8.41 108.99,8.38 108.2,8.38 107.7,7.87 JP3.6
A1_MUX  (via drill 0.25)
  Top 0.203: U21.2 110.39,9.27 109.65,9.27 109.51,9.16 R37.R3_1 107.84,9.16 107.82,9.14 109.02,9.14 | 109.02,9.14 109.12,9.16 | 109.02,9.14 v109.02,9.45 109.02,9.27
  Bottom 0.203: v109.02,9.45 108.13,9.45 107.82,9.14 JP3.7
A2_MUX  (via drill 0.25)
  Top 0.203: 109.02,10.16 110.11,10.16 110.11,9.78 110.36,9.78 U21.1 | R37.R4_1 108.16,10.12 108.2,10.16 109.02,10.16 | 109.02,10.16 v109.02,10.54
  Bottom 0.203: v109.02,10.54 106.93,10.54 JP3.8
ALERTB  (via drill 0.25)
  Top 0.203: U10.L3 U10.L2 v51.69,16.76 | v51.69,25.65 U10.E2 | v46.74,18.03 46.74,19.68 46.35,20.07 46.35,20.57 46.74,20.95 v46.74,25.65 | v105.54,17.4 105.54,16.38 105.16,16 98.42,16 95.76,18.67 73.91,18.67 v73.91,19.18
  Route2 0.203: v73.91,19.18 63.25,19.18 60.71,16.64 53.98,16.64 53.34,16 52.45,16 v51.69,16.76
  Route15 0.203: v46.74,25.65 v51.69,25.65
  Bottom 0.203: 105.92,17.4 105.92,14.99 106.43,14.48 106.43,12.19 107.31,11.3 109.47,11.3 109.98,10.79 109.98,8.26 108.33,6.6 108.33,3.72 JP2.3 | JP1.3 108.31,39.13 108.2,39.12 108.2,38.1 106.81,38.1 105.28,36.58 105.28,33.78 105.03,33.53 105.03,20.57 105.92,19.68 105.92,17.4 | TP19.TP 12.06,19.56 12.7,20.07 12.7,24.38 | v46.74,18.03 46.74,16.76 47.5,16 48.77,16 49.53,16.76 v51.69,16.76 | U24.1 16.91,23.99 16.51,24.38 12.7,24.38 | 12.7,24.38 12.7,29.46 14.22,30.99 41.4,30.99 v46.74,25.65 | v105.54,17.4 105.92,17.4
CTRL  (via drill 0.25)
  Top 0.178: U10.E3 52.96,24.38 51.05,24.38
  Top 0.203: C36.1 116.97,10.03 117.35,10.41 118.75,10.41 119,10.67 S1.5 | 51.05,24.38 U10.E1 | v49.78,18.03 50.42,17.4 U10.L1 U10.M1 | 51.05,24.38 U10.F1 v50.42,23.11 | 51.05,24.38 48.39,24.38 48.39,22.99 48.64,22.73 48.64,18.03 v48.51,18.03
  Top 0.406: S1.5 S1.2
  Route15 0.203: v104.78,18.67 105.79,18.67 107.44,17.02 107.44,16 108.71,14.73 113.16,14.73 113.67,15.24 114.94,15.24 116.59,13.59 117.22,13.59 118.87,11.94 S1.5 | v49.78,18.03 v48.51,18.03
  Bottom 0.203: 104.39,18.67 104.27,18.8 104.27,34.04 104.52,34.29 104.52,37.08 105.16,37.72 105.16,41.15 | 104.39,18.67 v104.78,18.67 | 104.39,17.78 104.39,15.24 105.66,13.97 105.66,12.45 105.28,12.06 105.28,4.95 105.16,4.83 105.16,1.91 105.41,1.65 106.27,1.65 JP2.2 | 105.16,41.15 106.27,41.15 JP1.2 | R135.2 105.16,43.56 105.16,41.15 | 104.39,17.78 93.34,17.78 91.82,16.26 77.85,16.26 76.96,17.14 75.44,17.14 74.55,16.26 69.85,16.26 69.6,16.51 69.6,19.18 67.06,21.72 65.53,21.72 63.5,23.75 60.33,23.75 59.94,23.37 56.52,23.37 56.13,23.75 U10.F1 v50.42,23.11 | 104.39,17.78 104.39,18.67
CTRL_P
  Bottom 0.203: R135.1 107.4,43.22 107.44,43.18 112.27,43.18 113.26,42.19 113.26,38.38 114.55,37.08 TP12.TP
DACP_CH0  (via drill 0.25)
  Top 0.178: v55.5,25.65 58.04,25.65 U10.E7
  Top 0.203: v21.72,30.23 VSNSN47.1
  Route15 0.203: v21.72,30.23 21.97,30.48 42.04,30.48 44.32,28.19 48.01,28.19 49.91,26.29 52.32,26.29 52.96,25.65 v55.5,25.65
  Bottom 0.203: R117.2 21.97,33.91 21.72,33.91
  Bottom 0.406: VSNSN47.1 21.72,33.91
DACP_CH1  (via drill 0.25)
  Top 0.203: v61.85,24.38 U10.F10 | v33.27,26.04 VSNSN45.1
  Bottom 0.203: R115.2 33.53,33.91 33.27,33.91 | v61.85,24.38 60.33,24.38 59.69,23.75 56.9,23.75 56.26,24.38 44.96,24.38 43.31,26.04 v33.27,26.04
  Bottom 0.406: VSNSN45.1 33.27,33.91
DACP_CH2  (via drill 0.25)
  Top 0.203: v61.85,25.65 U10.E10 | v44.83,25.65 VSNSN43.1
  Bottom 0.203: R113.2 45.09,33.91 44.83,33.91 | v61.85,25.65 61.21,25.02 45.47,25.02 v44.83,25.65
  Bottom 0.406: VSNSN43.1 44.83,33.91
DACP_CH3  (via drill 0.25)
  Top 0.203: v61.85,26.92 U10.D10
  Route15 0.203: v61.85,26.92 61.21,27.56 59.05,27.56 57.02,29.59 57.02,31.62 VSNSN41.1
  Bottom 0.203: R111.2 56.64,33.91 56.39,33.91
  Bottom 0.406: VSNSN41.1 56.39,33.91
DACP_CH4  (via drill 0.25)
  Top 0.203: U10.C10 v63.12,26.92 | v67.94,27.81 VSNSN39.1
  Route15 0.203: v63.12,26.92 63.75,27.56 67.94,27.56 v67.94,27.81
  Bottom 0.203: R109.2 68.2,33.91 67.94,33.91
  Bottom 0.406: VSNSN39.1 67.94,33.91
DACP_CH5  (via drill 0.25)
  Top 0.203: v63.12,28.19 U10.B10 | v79.5,28.96 VSNSN37.1
  Route15 0.203: v63.12,28.19 62.48,27.56 62.48,26.54 62.74,26.29 63.75,26.29 64.39,26.92 67.94,26.92 68.96,27.94 78.99,27.94 79.5,28.45 v79.5,28.96
  Bottom 0.203: R107.2 79.76,33.91 79.5,33.91
  Bottom 0.406: VSNSN37.1 79.5,33.91
DACP_CH6  (via drill 0.25)
  Top 0.203: U10.A10 v63.12,30.73 | v91.06,30.73 VSNSN35.1
  Route15 0.203: v63.12,30.73 63.12,30.23 63.63,29.72 72.77,29.72 73.79,30.73 86.74,30.73 87.38,30.1 90.68,30.1 90.81,30.1 91.06,30.35 v91.06,30.73
  Bottom 0.203: R105.2 91.31,33.91 91.06,33.91
  Bottom 0.406: VSNSN35.1 91.06,33.91
DACP_CH7  (via drill 0.25)
  Top 0.203: v58.04,29.46 U10.B7 | v102.62,30.73 VSNSN33.1
  Bottom 0.203: R103.2 102.87,33.91 102.62,33.91 | v58.04,29.46 58.67,30.1 84.84,30.1 85.47,29.46 92.46,29.46 93.98,30.99 102.62,30.99 v102.62,30.73
  Bottom 0.406: VSNSN33.1 102.62,33.91
DACP_CH8  (via drill 0.25)
  Top 0.203: v58.04,18.03 U10.L7
  Route15 0.203: v58.04,18.03 58.67,18.67 58.67,19.68 58.42,19.94 53.59,19.94 52.32,21.21 47.88,21.21 47.37,21.72 45.47,21.72 44.2,20.45 44.2,18.54 43.81,18.16 36.96,18.16 35.31,16.51 25.65,16.51 24.38,15.24 14.61,15.24 14.1,14.73 VSNSN32.1
  Bottom 0.203: R97.2 13.21,12.45 13.46,12.45
  Bottom 0.406: 13.46,12.45 13.46,13.72 13.84,14.1 VSNSN32.1
DACP_CH9  (via drill 0.25)
  Top 0.203: v58.67,13.97 58.67,14.61 58.93,14.86 60.83,14.86 61.34,15.37 61.72,15.37 U10.M10
  Route15 0.203: v58.67,13.97 57.4,15.24 28.19,15.24 27.81,14.86 25.4,14.86 25.02,14.48 VSNSN30.1
  Bottom 0.203: R95.2 24.77,12.45 25.02,12.45
  Bottom 0.406: 25.02,12.45 VSNSN30.1
DACP_CH10  (via drill 0.25)
  Top 0.203: v63.12,18.03 U10.L10 | VSNSN28.1 37.47,14.99 v37.47,17.02
  Route15 0.203: v63.12,18.03 63.12,17.78 62.74,17.4 58.93,17.4 58.42,16.89 53.72,16.89 53.21,17.4 47.24,17.4 47.12,17.27 37.72,17.27 v37.47,17.02
  Bottom 0.203: R93.2 36.32,12.45 36.58,12.45
  Bottom 0.406: 36.58,12.45 VSNSN28.1
DACP_CH11  (via drill 0.25)
  Top 0.203: v61.85,19.3 U10.K10 | VSNSN26.1 v48.13,16.76
  Bottom 0.203: R91.2 47.88,12.45 48.13,12.45 | v61.85,19.3 61.21,19.94 57.66,19.94 55.12,17.4 48.77,17.4 v48.13,16.76
  Bottom 0.406: 48.13,12.45 VSNSN26.1
DACP_CH12
  Top 0.178: U10.J10 63.12,19.3 64.14,19.3 64.39,19.56 64.39,20.57 66.8,20.57
  Top 0.203: 66.8,20.57 68.2,19.18 68.2,16.76 66.29,14.86 61.47,14.86 60.71,14.1 VSNSN24.1
  Bottom 0.203: R89.2 59.44,12.45 59.69,12.45
  Bottom 0.406: 59.69,12.45 VSNSN24.1
DACP_CH13  (via drill 0.25)
  Top 0.203: v63.12,20.57 U10.H10 | VSNSN22.1 v71.25,17.02
  Route15 0.203: v71.25,17.02 71.25,16.76 69.85,16.76 69.6,17.02 69.6,18.92 68.58,19.94 63.75,19.94 v63.12,20.57
  Bottom 0.203: R87.2 70.99,12.45 71.25,12.45
  Bottom 0.406: 71.25,12.45 VSNSN22.1
DACP_CH14  (via drill 0.25)
  Top 0.203: 82.8,14.48 VSNSN20.1 v82.8,17.53 | U10.G10 v63.12,23.11
  Route15 0.203: v63.12,23.11 64.64,21.59 68.83,21.59 72.39,18.03 77.6,18.03 78.36,17.27 82.8,17.27 v82.8,17.53
  Bottom 0.203: R85.2 82.55,12.45 82.8,12.45
  Bottom 0.406: VSNSN20.1 82.8,12.45
DACP_CH15  (via drill 0.25)
  Top 0.203: v58.04,21.84 U10.H7
  Bottom 0.203: R83.2 94.11,12.45 94.36,12.45 | v58.04,21.84 58.67,22.48 59.56,22.48 60.07,21.97 62.87,21.97 64.39,20.45 67.06,20.45 68.71,18.8 68.71,15.62 69.09,15.24 92.58,15.24 93.6,16.26 94.23,16.26 94.61,15.88 94.61,14.99 94.36,14.73 VSNSN18.1
  Bottom 0.406: VSNSN18.1 94.36,12.45
EESCL
  Top 0.203: 123.7,6.1 123.44,6.35 R47.1 124.26,6.35 | U22.1 124.04,1.59 124.26,1.78 124.26,6.35 | 124.26,6.35 124.26,6.66 124.84,7.24 124.84,8 125.09,8.26 129.89,8.26 130.4,8.76 130.4,10.29 129.95,10.73 128.24,10.73 J2.11 127.32,9.65
EESDA
  Top 0.203: 123.44,3.43 U22.3 123.38,3.49 123.38,4.76 123.44,4.83 R57.1 122.56,4.83 122.56,7.06 122.68,7.19 124.18,7.19 124.33,7.34 124.33,8.26 124.71,8.64 129.13,8.64 129.41,8.89 129.41,9.65 J2.12
EEVCC  (via drill 0.25)
  Top 0.203: 125.04,20.77 124.43,20.77 C24.1
  Top 0.254: U11.8 U11.7
  Top 0.406: R57.2 R47.2 121.67,6.35 | U22.4 120.58,3.49 120.9,3.56 | 120.9,4.79 R57.2 | 120.9,3.56 120.78,3.56 | 120.9,4.79 120.9,4.83 | 120.9,3.56 120.9,4.79 | R57.2 120.9,4.83 | 120.9,4.83 v120.52,4.83 | 121.67,6.35 121.58,6.35 | 121.67,6.35 121.67,7.87 C35.1
  Top 0.813: 130.14,37.97 130.25,37.95 130.2,37.82 130.3,37.85 130.3,22.61 130.18,22.48 130.12,22.42
  Top 1.016: 130.14,37.97 129.25,38.86 125.86,38.86 125.09,39.62 121.03,39.62 119.76,40.89 119.76,42.55 119.38,42.93 112.78,42.93 112.25,42.4 112.25,41.15 JP1.8 | 130.18,22.48 125.86,22.48 v125.73,22.99 v125.73,21.84 125.86,21.59 125.04,20.77 U11.8
  Route15 0.406: v114.3,19.56 115.82,19.56 118.11,21.84 v125.73,21.84
  Bottom 0.406: D1.2 115.2,19.8 114.81,19.56 v114.3,19.56
  Bottom 0.813: J2.1 127.24,19.7 127.22,19.68 125.83,19.68 arc60 125.73,19.68 v125.73,21.84 v125.73,22.99
  pour Bottom (no thermals): 111.51,2.92 119,2.92 119.76,3.68 119.76,18.29 122.3,20.83 128.11,20.83 128.11,18.92 123.95,18.92 121.54,16.51 121.54,0.76 111.51,0.76
  pour Top (no thermals): 121.92,21.46 124.84,21.46 125.22,21.84 125.22,23.5 126.62,23.5 126.62,21.72 125.09,20.19 121.92,20.19
FAULT  (via drill 0.25)
  Top 0.203: 41.02,18.92 41.06,18.92 R31.2
  Top 0.254: 39.62,18.92 SW2.SW1 | 39.62,18.92 41.02,18.92 41.02,19.81 R29.2 | v39.62,19.68 39.62,18.92
  Bottom 0.254: v39.62,19.68 39.75,19.56 39.75,16.18 Q9.1
FAULTB  (via drill 0.25)
  Top 0.203: 54.23,27.56 U10.C4 | U10.D4 U10.D3 54.23,26.29 v54.23,28.19 54.23,27.56 | 54.23,27.56 U10.C3 | v45.59,19.94 45.59,21.97 45.34,22.23 45.34,22.73 45.59,22.99 v45.59,28.83 | 54.23,19.94 v54.23,20.57 54.23,18.67 | 54.23,19.94 U10.J3 | 54.23,18.67 U10.K3 | 54.23,18.67 U10.K4 U10.L4 | 54.23,19.94 U10.J4
  Route15 0.203: v54.23,20.57 59.31,20.57 60.07,21.34 60.83,21.34 62.99,19.18 68.07,19.18 68.71,18.54 68.71,16.26 68.96,16 75.31,16 75.82,16.51 76.58,16.51 77.47,15.62 92.33,15.62 93.22,16.51 94.87,16.51 95.76,15.62 103.89,15.62 104.14,15.88 104.14,19.43 104.39,19.68 v104.9,19.68
  Bottom 0.203: U24.3 15.61,22.49 15.88,22.23 15.88,15.37 | JP2.1 106.01,3.72 105.92,3.81 105.92,6.35 105.79,6.48 105.79,11.94 106.05,12.19 106.05,14.22 104.78,15.49 104.78,17.65 105.54,18.41 105.54,19.43 105.28,19.68 v104.9,19.68 104.65,19.68 104.65,33.78 104.9,34.04 104.9,36.83 106.3,38.23 106.3,39.13 JP1.1 | v54.23,28.19 53.59,28.83 v45.59,28.83 | v54.23,20.57 52.96,20.57 52.2,21.34 46.48,21.34 45.59,20.45 v45.59,19.94 45.59,17.4 45.21,17.02 41.91,17.02 41.66,16.76 41.66,15.62 41.4,15.37 28.19,15.37 27.43,16.13 26.8,16.13 26.04,15.37 15.88,15.37 | TP21.TP 9.27,14.35 10.29,15.37 15.88,15.37
FB_LTC3604
  Top 0.203: 113.45,23.75 R25.2 113.58,24.42 113.79,24.64 114.43,24.64 114.68,24.89 114.68,27.05 114.43,27.3 114.43,28.96 114.03,29.44 U9.11
  Top 0.305: R28.1 C23.1 113.45,23.75 | R25.2 C20.2
GND  (via drill 0.25)
  Top 0.203: v21.59,13.72 v22.61,13.72 | C27.2 v21.59,13.72 | v21.59,13.72 v20.57,13.72 | v21.59,13.72 21.59,12.2 | R48.1 14.44,6.39 14.35,6.1 | v33.15,13.72 v34.16,13.72 | C28.2 v33.15,13.72 | v33.15,13.72 v32.13,13.72 | v33.15,13.72 33.15,12.2 | R49.1 26,6.39 25.91,6.1 | v44.7,13.72 v45.72,13.72 | C29.2 v44.7,13.72 | v44.7,13.72 v43.69,13.72 | v44.7,13.72 44.7,12.2 | R50.1 37.55,6.39 37.47,6.1 | v56.26,13.72 v57.28,13.72 | C30.2 v56.26,13.72 | v56.26,13.72 v55.24,13.72 | v56.26,13.72 56.26,12.2 | R51.1 49.11,6.39 49.02,6.1 | v67.82,13.72 v68.83,13.72 | C31.2 v67.82,13.72 | v67.82,13.72 v66.8,13.72 | v67.82,13.72 67.82,12.2 | R52.1 60.67,6.39 60.58,6.1 | v79.38,13.72 v80.39,13.72 | C32.2 v79.38,13.72 | v79.38,13.72 v78.36,13.72 | v79.38,13.72 79.38,12.2 | R53.1 72.22,6.39 72.14,6.1 | v90.93,13.72 v91.95,13.72 | C33.2 v90.93,13.72 | v90.93,13.72 v89.92,13.72 | v90.93,13.72 90.93,12.2 | R54.1 83.78,6.39 83.69,6.1 | v102.49,13.72 v103.5,13.72 | C34.2 v102.49,13.72 | v102.49,13.72 v101.47,13.72 | v102.49,13.72 102.49,12.2 | R55.1 95.34,6.39 95.25,6.1 | LED3.N 107.94,19.55 LED3.N 108.58,19.56 108.84,19.81 v108.84,20.07 | v12.57,32.64 v13.59,32.64 | v13.59,32.64 C9.2 | v13.59,32.64 v14.61,32.64 | v13.59,32.64 13.59,34.16 | R9.1 20.74,39.97 20.83,40.26 | v24.13,32.64 v25.15,32.64 | v25.15,32.64 C10.2 | v25.15,32.64 v26.16,32.64 | v25.15,32.64 25.15,34.16 | R10.1 32.3,39.97 32.38,40.26 | v35.69,32.64 v36.7,32.64 | v36.7,32.64 C11.2 | v36.7,32.64 v37.72,32.64 | v36.7,32.64 36.7,34.16 | R11.1 43.85,39.97 43.94,40.26 | v47.24,32.64 v48.26,32.64 | v48.26,32.64 C12.2 | v48.26,32.64 v49.28,32.64 | v48.26,32.64 48.26,34.16 | R12.1 55.41,39.97 55.5,40.26 | v58.8,32.64 v59.82,32.64 | v59.82,32.64 C13.2
  Top 0.203: v59.82,32.64 v60.83,32.64 | v59.82,32.64 59.82,34.16 | R13.1 66.97,39.97 67.06,40.26 | v70.36,32.64 v71.37,32.64 | v71.37,32.64 C14.2 | v71.37,32.64 v72.39,32.64 | v71.37,32.64 71.37,34.16 | R14.1 78.53,39.97 78.61,40.26 | v81.92,32.64 v82.93,32.64 | v82.93,32.64 C15.2 | v82.93,32.64 v83.95,32.64 | v82.93,32.64 82.93,34.16 | R15.1 90.08,39.97 90.17,40.26 | v93.47,32.64 v94.49,32.64 | v94.49,32.64 C16.2 | v94.49,32.64 v95.5,32.64 | v94.49,32.64 94.49,34.16 | R16.1 101.64,39.97 101.73,40.26 | v56.77,26.92 56.77,26.29 | v52.96,23.11 52.96,23.75 U10.F3 | v64.39,18.03 63.75,18.03 U10.K11 | U10.M2 v52.96,16.76
  Top 0.406: 14.35,6.1 14.48,6.22 14.73,6.22 | v15.49,6.22 14.44,6.22 R48.1 | 25.91,6.1 26.04,6.22 26.29,6.22 | v27.05,6.22 26,6.22 R49.1 | 37.47,6.1 37.59,6.22 37.85,6.22 | v38.61,6.22 37.55,6.22 R50.1 | 49.02,6.1 49.15,6.22 49.4,6.22 | v50.16,6.22 49.11,6.22 R51.1 | 60.58,6.1 60.71,6.22 60.96,6.22 | v61.72,6.22 60.67,6.22 R52.1 | 72.14,6.1 72.26,6.22 72.52,6.22 | v73.28,6.22 72.22,6.22 R53.1 | 83.69,6.1 83.82,6.22 84.07,6.22 | v84.84,6.22 83.78,6.22 R54.1 | 95.25,6.1 95.38,6.22 95.63,6.22 | v96.39,6.22 95.34,6.22 R55.1 | 20.83,40.26 20.7,40.13 20.45,40.13 | v19.68,40.13 20.74,40.13 R9.1 | 32.38,40.26 32.26,40.13 32,40.13 | v31.24,40.13 32.3,40.13 R10.1 | 43.94,40.26 43.81,40.13 43.56,40.13 | v42.8,40.13 43.85,40.13 R11.1 | 55.5,40.26 55.37,40.13 55.12,40.13 | v54.36,40.13 55.41,40.13 R12.1 | 67.06,40.26 66.93,40.13 66.67,40.13 | v65.91,40.13 66.97,40.13 R13.1 | 78.61,40.26 78.49,40.13 78.23,40.13 | v77.47,40.13 78.53,40.13 R14.1 | 90.17,40.26 90.04,40.13 89.79,40.13 | v89.03,40.13 90.08,40.13 R15.1 | 101.73,40.26 101.6,40.13 101.35,40.13 | v100.58,40.13 101.64,40.13 R16.1
  Top 0.813: v66.8,13.72 67.06,13.72
  Bottom 0.203: 22.99,3.03 Q8.2 | 22.99,3.03 22.99,3.05 | v22.99,2.29 22.99,3.03 | 34.54,3.03 Q7.2 | 34.54,3.03 34.54,3.05 | v34.54,2.29 34.54,3.03 | 46.1,3.03 Q6.2 | 46.1,3.03 46.1,3.05 | v46.1,2.29 46.1,3.03 | 57.66,3.03 Q5.2 | 57.66,3.03 57.66,3.05 | v57.66,2.29 57.66,3.03 | 69.22,3.03 Q4.2 | 69.22,3.03 69.22,3.05 | v69.22,2.29 69.22,3.03 | 80.77,3.03 Q3.2 | 80.77,3.03 80.77,3.05 | v80.77,2.29 80.77,3.03 | 92.33,3.03 Q2.2 | 92.33,3.03 92.33,3.05 | v92.33,2.29 92.33,3.03 | 103.89,3.03 Q1.2 | 103.89,3.03 103.89,3.05 | v103.89,2.29 103.89,3.03 | v108.84,20.07 108.58,19.81 | Q17.2 12.19,43.32 | 12.19,43.32 12.19,43.31 | 12.19,43.32 v12.19,44.07 | Q16.2 23.75,43.32 | 23.75,43.32 23.75,43.31 | 23.75,43.32 v23.75,44.07 | Q15.2 35.31,43.32 | 35.31,43.32 35.31,43.31 | 35.31,43.32 v35.31,44.07 | Q14.2 46.86,43.32 | 46.86,43.32 46.86,43.31 | 46.86,43.32 v46.86,44.07 | Q13.2 58.42,43.32 | 58.42,43.32 58.42,43.31 | 58.42,43.32 v58.42,44.07 | Q12.2 69.98,43.32 | 69.98,43.32 69.98,43.31 | 69.98,43.32 v69.98,44.07 | Q11.2 81.53,43.32 | 81.53,43.32 81.53,43.31 | 81.53,43.32 v81.53,44.07 | Q10.2 93.09,43.32 | 93.09,43.32 93.09,43.31 | 93.09,43.32 v93.09,44.07
  Bottom 0.406: 125.95,7.34 125.95,17.78 127.36,17.78 J2.3
  other vias: 112.65,8.76 109.73,15.49 114.55,14.22 111.51,29.21 125.6,7.49 121.79,2.54 119.51,5.21 106.17,25.02 106.17,26.04 117.47,18.29 124.84,18.03 115.57,25.15 116.71,25.15 117.86,25.15 13.84,16.13 16.89,18.92 70.23,17.4 51.69,18.03 49.53,28.19 49.02,26.29 49.78,22.48 64.39,30.73 63.12,15.49
  pour Top (no thermals): 19.56,14.35 23.11,14.35 23.11,11.05 18.29,11.05 17.65,11.68 17.65,13.34 18.29,13.34 18.29,11.94 18.54,11.68 19.3,11.68 19.56,11.94
  pour Bottom (no thermals): 19.56,14.35 23.11,14.35 23.11,11.18 19.94,11.18 19.56,11.56
  pour Bottom (no thermals): 11.81,5.08 11.81,9.78 13.97,9.78 14.35,10.16 14.35,11.3 16.26,11.3 16.26,9.78 15.88,9.4 15.88,6.1 14.86,5.08
  pour Top (no thermals): 31.11,14.35 34.67,14.35 34.67,11.05 29.84,11.05 29.21,11.68 29.21,13.34 29.84,13.34 29.84,11.94 30.1,11.68 30.86,11.68 31.11,11.94
  pour Bottom (no thermals): 31.11,14.35 34.67,14.35 34.67,11.18 31.5,11.18 31.11,11.56
  pour Bottom (no thermals): 23.62,5.08 23.62,6.73 24,7.11 24,9.78 25.53,9.78 25.91,10.16 25.91,11.3 27.81,11.3 27.81,9.78 27.43,9.4 27.43,6.1 26.42,5.08
  pour Top (no thermals): 42.67,14.35 46.23,14.35 46.23,11.05 41.4,11.05 40.77,11.68 40.77,13.34 41.4,13.34 41.4,11.94 41.66,11.68 42.42,11.68 42.67,11.94
  pour Bottom (no thermals): 42.67,14.35 46.23,14.35 46.23,11.18 43.05,11.18 42.67,11.56
  pour Bottom (no thermals): 35.18,5.08 35.18,6.73 35.56,7.11 35.56,9.78 37.08,9.78 37.47,10.16 37.47,11.3 39.37,11.3 39.37,9.78 38.99,9.4 38.99,6.1 37.97,5.08
  pour Top (no thermals): 54.23,14.35 57.78,14.35 57.78,11.05 52.96,11.05 52.32,11.68 52.32,13.34 52.96,13.34 52.96,11.94 53.21,11.68 53.98,11.68 54.23,11.94
  pour Bottom (no thermals): 54.23,14.35 57.78,14.35 57.78,11.18 54.61,11.18 54.23,11.56
  pour Bottom (no thermals): 46.74,5.08 46.74,6.73 47.12,7.11 47.12,9.78 48.64,9.78 49.02,10.16 49.02,11.3 50.93,11.3 50.93,9.78 50.55,9.4 50.55,6.1 49.53,5.08
  pour Top (no thermals): 65.79,14.35 69.34,14.35 69.34,11.05 64.52,11.05 63.88,11.68 63.88,13.34 64.52,13.34 64.52,11.94 64.77,11.68 65.53,11.68 65.79,11.94
  pour Bottom (no thermals): 65.79,14.35 69.34,14.35 69.34,11.18 66.17,11.18 65.79,11.56
  pour Bottom (no thermals): 58.29,5.08 58.29,6.73 58.67,7.11 58.67,9.78 60.2,9.78 60.58,10.16 60.58,11.3 62.48,11.3 62.48,9.78 62.1,9.4 62.1,6.1 61.09,5.08
  pour Top (no thermals): 77.34,14.35 80.9,14.35 80.9,11.05 76.07,11.05 75.44,11.68 75.44,13.34 76.07,13.34 76.07,11.94 76.33,11.68 77.09,11.68 77.34,11.94
  pour Bottom (no thermals): 77.34,14.35 80.9,14.35 80.9,11.18 77.72,11.18 77.34,11.56
  pour Bottom (no thermals): 69.85,5.08 69.85,6.73 70.23,7.11 70.23,9.78 71.75,9.78 72.14,10.16 72.14,11.3 74.04,11.3 74.04,9.78 73.66,9.4 73.66,6.1 72.64,5.08
  pour Top (no thermals): 88.9,14.35 92.46,14.35 92.46,11.05 87.63,11.05 87,11.68 87,13.34 87.63,13.34 87.63,11.94 87.88,11.68 88.65,11.68 88.9,11.94
  pour Bottom (no thermals): 88.9,14.35 92.46,14.35 92.46,11.18 89.28,11.18 88.9,11.56
  pour Bottom (no thermals): 81.41,5.08 81.41,6.73 81.79,7.11 81.79,9.78 83.31,9.78 83.69,10.16 83.69,11.3 85.6,11.3 85.6,9.78 85.22,9.4 85.22,6.1 84.2,5.08
  pour Top (no thermals): 100.46,14.35 104.01,14.35 104.01,11.05 99.19,11.05 98.55,11.68 98.55,13.34 99.19,13.34 99.19,11.94 99.44,11.68 100.2,11.68 100.46,11.94
  pour Bottom (no thermals): 100.46,14.35 104.27,14.35 104.27,11.18 100.84,11.18 100.46,11.56
  pour Bottom (no thermals): 92.96,5.08 92.96,6.73 93.34,7.11 93.34,9.78 94.87,9.78 95.25,10.16 95.25,11.3 97.16,11.3 97.16,9.78 96.77,9.4 96.77,6.1 95.76,5.08
  pour Route2 (no thermals): 0.89,45.59 0.89,3.05 3.17,0.76 130.65,0.76 130.65,45.59
  pour Bottom (no thermals): 11.94,32 103.89,32 103.89,41.27 104.27,41.27 104.27,44.58 103.89,44.58 103.89,45.59 130.65,45.59 130.65,0.76 122.05,0.76 122.05,16.38 124.08,18.41 128.49,18.41 128.52,21.34 122.3,21.34 122.3,28.19 123.95,29.84 123.95,33.15 122.56,34.42 120.65,34.42 120.52,34.54 120.52,41.91 119.76,42.67 117.73,42.67 117.09,42.04 117.09,37.34 116.46,36.7 116.46,25.91 118.36,25.91 118.36,24.38 116.46,24.38 116.46,3.3 111.12,3.3 111.12,0.76 104.27,0.76 104.27,14.35 11.81,14.35 11.81,5.08 11.3,5.08 11.3,1.78 11.81,1.78 11.81,0.76 0.89,0.76 0.89,45.59 11.81,45.59 11.81,41.53 11.3,41.53 11.3,35.81 11.94,35.18
  pour Top (no thermals): 104.01,14.35 65.91,14.35 65.91,30.86 50.29,30.86 50.29,14.35 11.81,14.35 11.81,0.76 1.78,0.76 0.89,1.65 0.89,45.59 11.81,45.59 11.81,32 105.16,32 105.16,26.42 106.3,26.42 106.55,26.16 106.55,19.18 127.13,19.18 127.13,27.56 124.08,27.56 124.08,32.77 122.43,34.29 119.63,34.29 118.62,33.27 109.35,33.27 109.35,32.38 105.16,32.38 105.16,32.13 104.01,32.13 104.01,45.59 130.65,45.59 130.65,0.76 104.01,0.76 104.01,6.35 104.52,6.35 104.52,11.05 104.01,11.05
  pour Top (no thermals): 110.74,29.84 113.92,29.84 114.43,29.34 114.43,28.19 124.08,28.19 124.08,27.56 118.24,27.56 118.24,24.26 123.06,24.26 123.83,23.5 124.71,23.5 124.71,21.97 124.59,21.84 111.51,21.84 111.51,25.02 110.74,25.02
  pour Bottom (no thermals): 23.37,41.27 23.37,36.58 21.21,36.58 20.83,36.2 20.83,35.05 18.92,35.05 18.92,36.58 19.3,36.96 19.3,40.26 20.32,41.27
  pour Top (no thermals): 15.62,32 11.94,32 11.94,35.31 16.89,35.31 17.53,34.67 17.53,33.02 16.89,33.02 16.89,34.42 16.64,34.67 15.88,34.67 15.62,34.42
  pour Bottom (no thermals): 15.62,32 12.06,32 12.06,35.18 15.24,35.18 15.62,34.8
  pour Bottom (no thermals): 34.92,41.27 34.92,36.58 32.77,36.58 32.38,36.2 32.38,35.05 30.48,35.05 30.48,36.58 30.86,36.96 30.86,40.26 31.88,41.27
  pour Top (no thermals): 27.18,32 23.62,32 23.62,35.31 28.45,35.31 29.08,34.67 29.08,33.02 28.45,33.02 28.45,34.42 28.19,34.67 27.43,34.67 27.18,34.42
  pour Bottom (no thermals): 27.18,32 23.62,32 23.62,35.18 26.8,35.18 27.18,34.8
  pour Bottom (no thermals): 46.48,41.27 46.48,36.58 44.32,36.58 43.94,36.2 43.94,35.05 42.04,35.05 42.04,36.58 42.42,36.96 42.42,40.26 43.43,41.27
  pour Top (no thermals): 38.73,32 35.18,32 35.18,35.31 40.01,35.31 40.64,34.67 40.64,33.02 40.01,33.02 40.01,34.42 39.75,34.67 38.99,34.67 38.73,34.42
  pour Bottom (no thermals): 38.73,32 35.18,32 35.18,35.18 38.35,35.18 38.73,34.8
  pour Bottom (no thermals): 58.04,41.27 58.04,36.58 55.88,36.58 55.5,36.2 55.5,35.05 53.59,35.05 53.59,36.58 53.98,36.96 53.98,40.26 54.99,41.27
  pour Top (no thermals): 50.29,32 46.74,32 46.74,35.31 51.56,35.31 52.2,34.67 52.2,33.02 51.56,33.02 51.56,34.42 51.31,34.67 50.55,34.67 50.29,34.42
  pour Bottom (no thermals): 50.29,32 46.74,32 46.74,35.18 49.91,35.18 50.29,34.8
  pour Bottom (no thermals): 69.6,41.27 69.6,36.58 67.44,36.58 67.06,36.2 67.06,35.05 65.15,35.05 65.15,36.58 65.53,36.96 65.53,40.26 66.55,41.27
  pour Top (no thermals): 61.85,32 58.29,32 58.29,35.31 63.12,35.31 63.75,34.67 63.75,33.02 63.12,33.02 63.12,34.42 62.87,34.67 62.1,34.67 61.85,34.42
  pour Bottom (no thermals): 61.85,32 58.29,32 58.29,35.18 61.47,35.18 61.85,34.8
  pour Bottom (no thermals): 81.15,41.27 81.15,36.58 78.99,36.58 78.61,36.2 78.61,35.05 76.71,35.05 76.71,36.58 77.09,36.96 77.09,40.26 78.11,41.27
  pour Top (no thermals): 73.41,32 69.85,32 69.85,35.31 74.68,35.31 75.31,34.67 75.31,33.02 74.68,33.02 74.68,34.42 74.42,34.67 73.66,34.67 73.41,34.42
  pour Bottom (no thermals): 73.41,32 69.85,32 69.85,35.18 73.03,35.18 73.41,34.8
  pour Bottom (no thermals): 92.71,41.27 92.71,36.58 90.55,36.58 90.17,36.2 90.17,35.05 88.27,35.05 88.27,36.58 88.65,36.96 88.65,40.26 89.66,41.27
